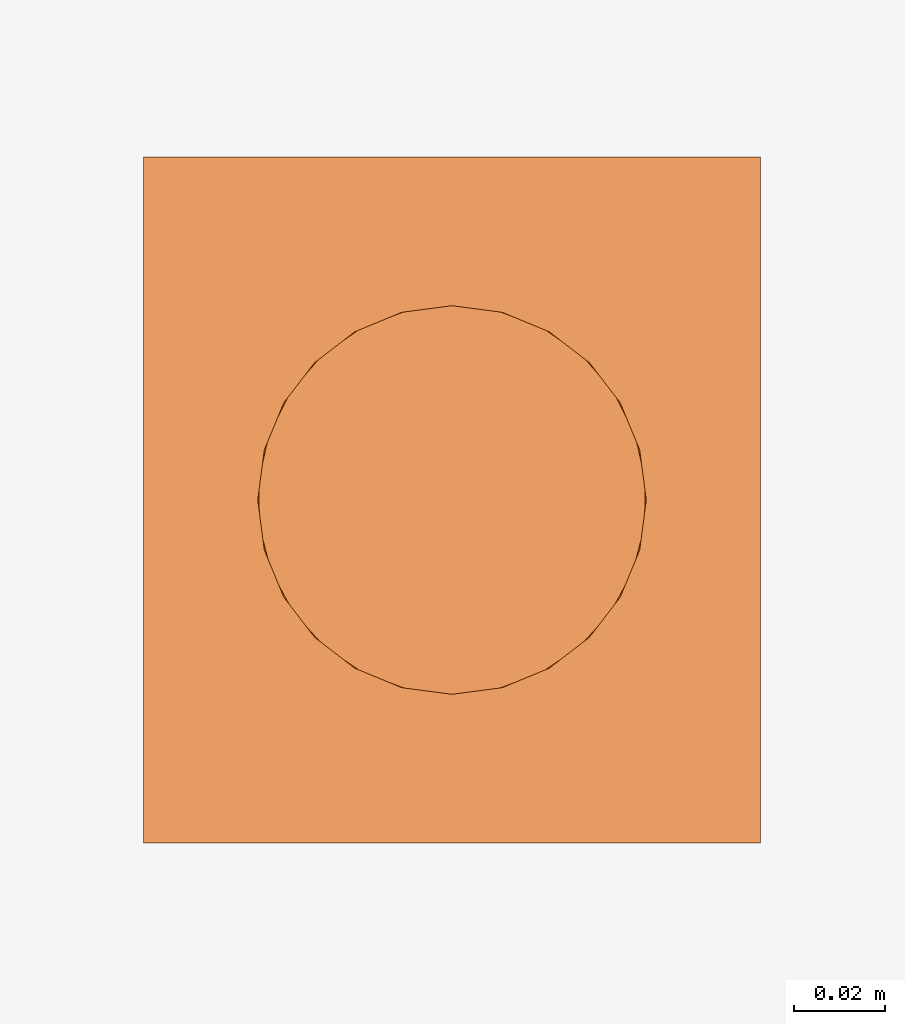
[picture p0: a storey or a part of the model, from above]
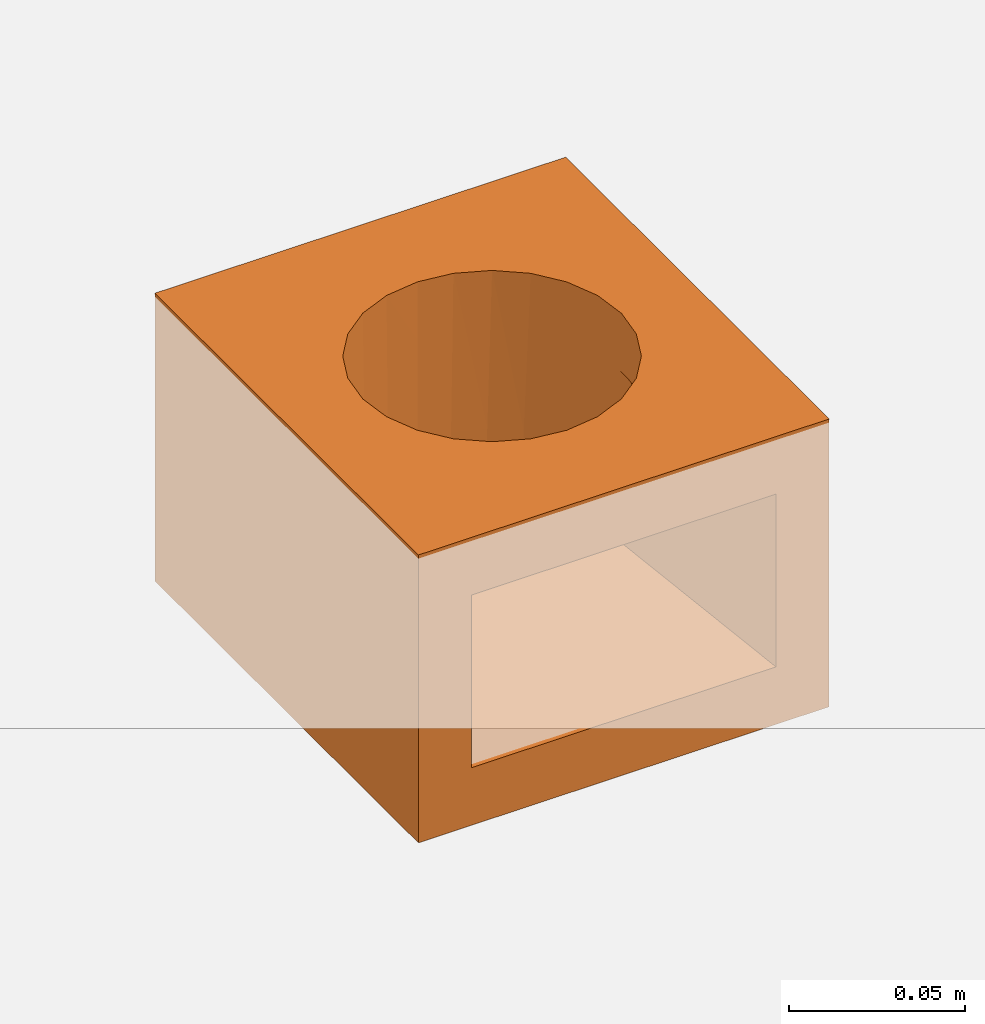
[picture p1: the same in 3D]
Properties of the parts of a building model (IFC2X3)

# File
Description: ViewDefinition [CoordinationView]
File name: 23451 - CFD0100 Downpipe connector - 100mm high.ifc
Time: 2013-10-16T12:21:18
Written by: Autodesk Revit 2013
Made in: 20120221_2030(x64)

# IfcProject, Project Number
LongName: Project Name; Phase: Project Status

# IfcSite, Default
RefLatitude: 42, 21, 30, 344238; RefLongitude: -71, -3, -35, -194702; RefElevation: 0 mm

# IfcBuilding
Pset_BuildingCommon - NumberOfStoreys: 1
Other - Project Address: ## Street City, State Zip; Project Status: Project Status; Project Name: Project Name; Client Name: Owner; Project Number: Project Number; Project Issue Date: Issue Date

# IfcBuildingStorey, Level 1
LongName: Level 1; Elevation: 0 mm
Constraints - Elevation Base: 0; Elevation: 0 mm
Graphics - Line Weight: 1; Symbol at End 1 Default: no; Symbol at End 2 Default: yes; Line Pattern: Center; Color: 0; Symbol: M_Level Head - Circle: M_Level Head - Circle
Identity Data - Name: Level 1; Structural: no; Building Story: yes
Dimensions - Computation Height: 0 mm

# IfcBuildingElementProxy: 23451 - CFD0100 Downpipe connector - 100mm high, Civil-Drainage-Channel-ACO-MultiDrain-M100D-Channel-System:23451 - CFD0100 Downpipe connector - 100mm high:23451 - CFD0100 Downpipe connector - 100mm high:1089344
In: Level 1
Material: Grey Polymer Concrete
Construction - 12614 - Grating - Slotted - Galvanised Steel - 1000mm Long: no; 23405 - Grating - Heelguard™ - Ductile Iron - 500mm Long: no; 12611 - Grating - Slotted - Galvanised Steel - 500mm Long: no; 23406 - Grating - Solid Cover - Ductile Iron - 500mm Long: no; 12673 - Grating - Intercept - Ductile Iron - 500mm Long: no; 23404 - Universal Endcap - Female End: no; 23408 - Grating - Slotted - Ductile Iron - 500mm Long: no; 23404 - Universal Endcap - Male End: no; 12619 - Grating - Mesh - Galvanised Steel - 500mm Long: no; 12680 - Grating - Heelguard™ - Composite Black - 500mm Long: no; 12666 - Grating - Perforated - Galvanised Steel - 1000mm Long: no; 12657 - Grating - Perforated - Galvanised Steel - 500mm long: no; 12656 - Grating - Perforated - Galvanised Steel - 1000mm long: no; 12610 - Grating - Slotted - Galvanised Steel - 1000mm Long: no; 23409 - Grating - ATec coated - Heelguard™ - Ductile Iron - 500mm Long: no; 12667 - Grating - Perforated - Galvanised Steel - 500mm Long: no; 12615 - Grating - Slotted - Galvanised Steel - 500mm Long: no; 12618 - Grating - Mesh - Galvanised Steel - 1000mm Long: no; 23450 - Downpipe connector 75mm Depth: no; Sloping Channel: no; Shallow Depth Channel with seal: no; 23451 - Downpipe connector 100mm Depth: yes; Grating 1000mm: no; 23452 - Kerb Outlet Half Batter: no; Sump Unit: no; 23453 - Kerb Outlet Bull Nose: no; Shallow Depth Channel: no; Constant Depth Channel: no; Constant Depth Junction Channel: no
Dimensions - FloorCut_Length: -150 mm; Length: 150 mm; EndCap Position: 150 mm; Volume: 1324098 mm3; Custom_Value_Length: 850 mm; ShallowInvDepth: 55 mm; InvDepth: 80 mm; ShallowOverallDepth: 75 mm; Length Drain: -1000 mm; EndCap_Height: 249 mm; SlopingInvertDepth: 125 mm; FloorCut_HorPosition: 67.5 mm; SlopingEndInvertDepth: 130 mm; EndCap_Female_Height: 249 mm; SlopingOverallDepth: 195 mm; Endcap_Void_Depth: 6000 mm; FloorCut_Width: 135 mm; SlopingEndOverallDepth: 200 mm; Depth: 150 mm; FloorCut_Depth: 100 mm
Constraints - Moves With Nearby Elements: no; Level: Level: Level 1
Phasing - Phase Created: New Construction
Pset_BuildingElementProxyCommon - Reference: 23451 - CFD0100 Downpipe connector - 100mm high
General - TagNumber: 0; SerialNumber: 0
Data - Invert Depth: N/A; Hydraulic Performance: N/A; Concrete Surround Volume - Load Class A 15 - Concrete Pavement: N/A; Pre-formed Outlet Ø: N/A; ACO Hydraulic Design Software: N/A; Channel C.S.A: N/A; Installation - Concrete Grade: N/A; Product Standard: N/A; Product Dimensions: 150mm x 135mm x 100mm (LxWxH); Product Weight: 3kg; Concrete Surround Volume - Load Class B 125 - C 250 - Concrete Pavement: N/A; Load Class: N/A; Concrete Surround Volume - Load Class D 400 - Concrete Pavement: N/A
Identity Data - Model Description: Channel drainage system; Watermark 1: This file is the property of ACO Technologies PLC; Watermarked With: BIM Manager Premium Suite; OmniClass Title: Rainwater Removal; Watermark 2: This file is watermarked and users are prohibited to reproduce, adapt, distribute this information; Maintenance guidelines: http://www.aco.co.uk/download.php?id=173; Product Page URL: http://www.aco.co.uk/product_detail.php?id=15; Product brochure: http://www.aco.co.uk/download.php?id=173; Telephone: +44 (0)1462 816666; Cost: 0; OmniClass Number: 23.70.50.24; Watermarked By: www.aco.co.uk; URL: www.aco.co.uk; Model: Channel drainage system; Type Comments: ACO MultiDrain M100D CFD0100 Downpipe Connector Grey; e-mail Technical: technical@aco.co.uk; Address: ACO Business Park, Hitchin Road, Shefford, Bedfordshire, United Kingdom SG17 5TE; Assembly Code: D2040; Price: POA - contact ACO; Installation guidelines: http://www.aco.co.uk/download.php?id=173; Manufacturer: ACO Technologies plc - ACO Water Management Division; Assembly Description: Rain Water Drainage; e-mail Sales: customersupport@aco.co.uk; Fax: +44 (0)1462 815895; Product Code: 23451
Model Properties - End Cap Product code 23404: N/A; Grating Product code 12667: N/A; Grating Product code 12615: N/A; Grating Product code 23405: N/A; Grating Product code 12666: N/A; Grating Product code 12611: N/A; Grating Product code 12610: N/A; Grating Product code 12656: N/A; Grating Product code 12673: N/A; Grating Product code 12614: N/A; Grating Product code 12680: N/A; Grating Product code 23408: N/A; Grating Product code 12618: N/A; Grating Product code 23406: N/A; Grating Product code 12657: N/A; Grating Product code 12619: N/A
Materials and Finishes - Channel Colour: Grey; Edge Rail Material: N/A; Edge Rail Colour: N/A; Channel Material: Vienite® Synthetic Resin Concrete; Edge Rail Finish: N/A
Other - CreatedBy: www.aco.co.uk; Revision: 1
Green Building Properties - Channel Recycled Material Content: 20% minimum; Edge Rail Recyclable: N/A; Edge Rail Recycled Material Content: N/A; Channel Recyclable: Fully recyclable

# IfcOpeningElement: Recess
In: Level 1
Structural - Structural: no; Enable Analytical Model: no
Phasing - Phase Created: New Construction
Constraints - Height Offset From Level: 0 mm; Related to Mass: no; Level: Level: Level 1; Room Bounding: yes
Dimensions - Thickness: 400 mm; Volume: 10809975000 mm3; Perimeter: 20800 mm; Area: 27030000 mm2
Materials and Finishes - Structural Material: Plant
Construction - Default Thickness: 400 mm; Function: 0
Graphics - Coarse Scale Fill Color: 0
Analytical Properties - Absorptance: 0.1; Roughness: 1

# IfcSlab: Floor:Generic Floor - 400mm, Floor:Generic Floor - 400mm:193825
In: Level 1
PredefinedType: FLOOR; Material: Plant 400 mm
Structural - Structural: no; Enable Analytical Model: no
Phasing - Phase Created: New Construction
Constraints - Height Offset From Level: 0 mm; Related to Mass: no; Level: Level: Level 1; Room Bounding: yes
Dimensions - Thickness: 400 mm; Volume: 10809975000 mm3; Perimeter: 20800 mm; Area: 27030000 mm2
Pset_SlabCommon - Reference: Generic Floor - 400mm; IsExternal: no; LoadBearing: yes
Materials and Finishes - Structural Material: Plant
Construction - Default Thickness: 400 mm; Function: 0
Graphics - Coarse Scale Fill Color: 0
Analytical Properties - Absorptance: 0.1; Roughness: 1
